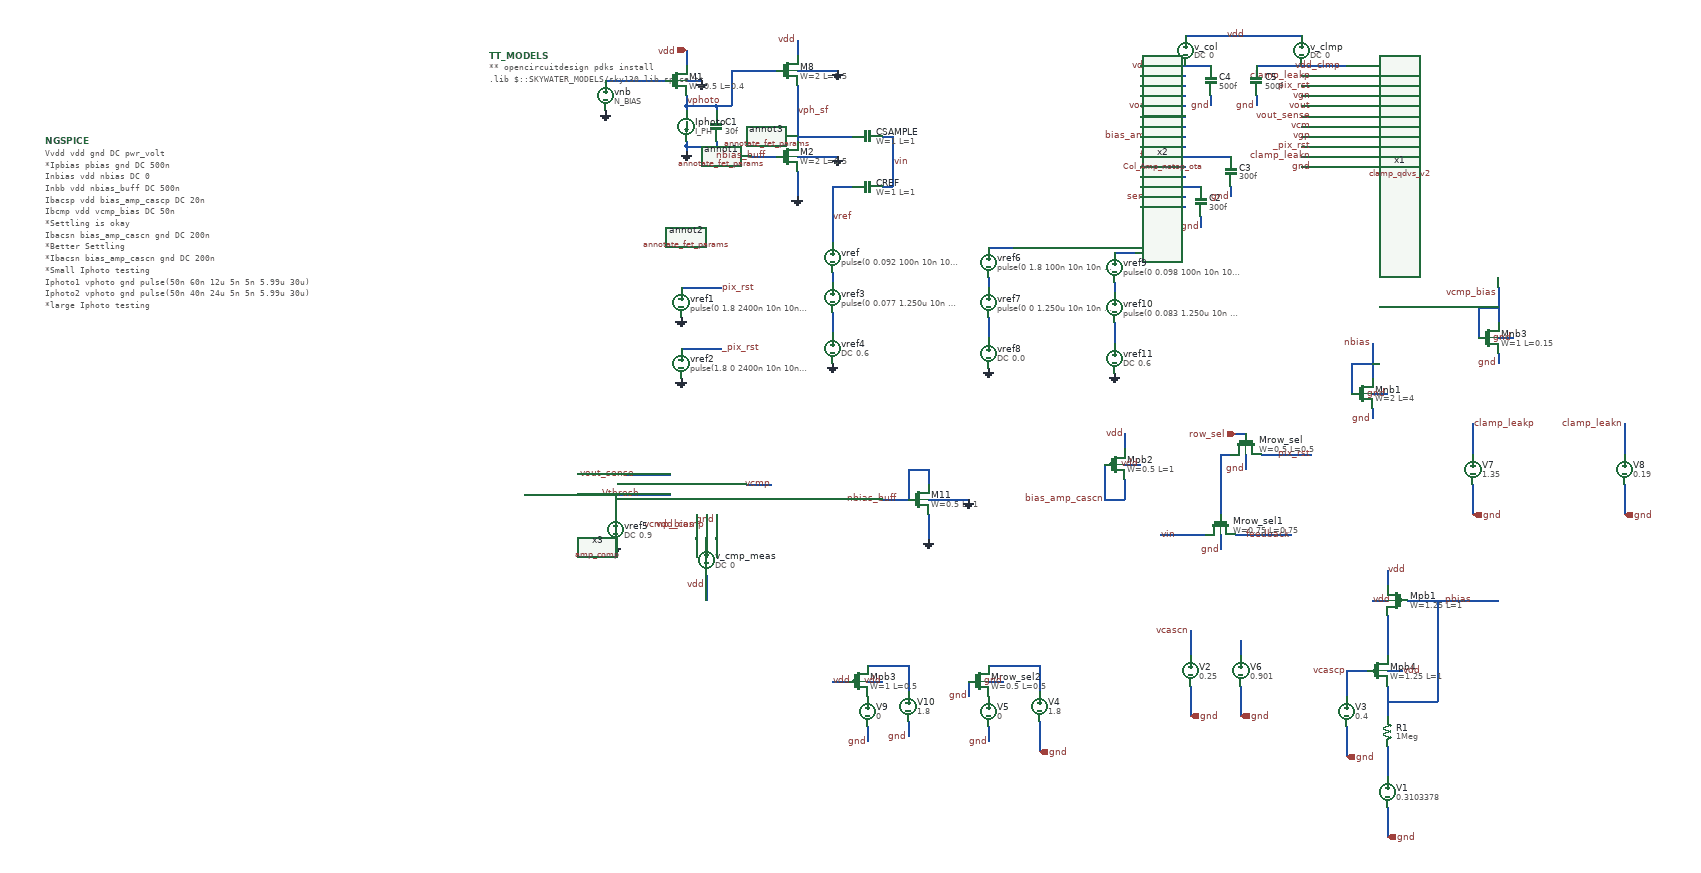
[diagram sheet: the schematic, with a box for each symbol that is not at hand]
v {xschem version=3.4.8RC file_version=1.3}
G {}
K {}
V {}
S {}
F {}
E {}
N -480 -190 -480 -180 {lab=GND}
N -480 -270 -480 -260 {lab=vphoto}
N -480 -380 -480 -350 {lab=vdd}
N -420 -270 -420 -260 {lab=vphoto}
N -480 -270 -420 -270 {lab=vphoto}
N -420 -200 -420 -190 {lab=GND}
N -480 -190 -420 -190 {lab=GND}
N -170 -210 -150 -210 {lab=vph_sf}
N -90 -110 -70 -110 {lab=vin}
N -70 -210 -70 -110 {lab=vin}
N -90 -210 -70 -210 {lab=vin}
N -480 -290 -480 -270 {lab=vphoto}
N -480 -200 -480 -190 {lab=GND}
N -480 -320 -450 -320 {lab=GND}
N -640 -320 -520 -320 {lab=#net1}
N -260 -210 -170 -210 {lab=vph_sf}
N -260 -310 -260 -230 {lab=vph_sf}
N -260 -230 -260 -200 {lab=vph_sf}
N -420 -270 -390 -270 {lab=vphoto}
N -390 -340 -390 -270 {lab=vphoto}
N -390 -340 -300 -340 {lab=vphoto}
N -260 -170 -180 -170 {lab=GND}
N -260 -400 -260 -370 {lab=vdd}
N -260 -140 -260 -90 {lab=GND}
N -350 -170 -300 -170 {lab=nbias_buff}
N -260 -340 -180 -340 {lab=GND}
N -490 90 -410 90 {lab=pix_rst}
N -490 210 -410 210 {lab=_pix_rst}
N -190 60 -190 80 {lab=#net2}
N -190 140 -190 180 {lab=#net3}
N -190 -110 -190 0 {lab=vref}
N -190 -110 -150 -110 {lab=vref}
N 420 -330 510 -330 {lab=pbias}
N 420 -310 510 -310 {lab=pbchk}
N 420 -290 510 -290 {lab=vcascp}
N 420 -270 510 -270 {lab=vout_sense}
N 420 -250 510 -250 {lab=pix_rst}
N 420 -230 510 -230 {lab=vcascn}
N 420 -210 510 -210 {lab=bias_amp_cascn}
N 420 -190 510 -190 {lab=gnd}
N 420 -170 510 -170 {lab=feedback}
N 420 -150 510 -150 {lab=nbias}
N 420 -130 510 -130 {lab=row_sel}
N 420 -110 510 -110 {lab=sense}
N 420 -90 510 -90 {lab=sense_local}
N 420 -70 510 -70 {lab=vin}
N 540 -50 540 -30 {lab=gnd}
N 510 -110 540 -110 {lab=sense}
N 510 -170 600 -170 {lab=feedback}
N 600 -110 600 -90 {lab=gnd}
N 420 -350 510 -350 {lab=vdd_col}
N 880 330 880 350 {lab=gnd}
N 880 300 910 300 {lab=gnd}
N 880 200 880 270 {lab=nbias}
N 840 240 880 240 {lab=nbias}
N 840 240 840 300 {lab=nbias}
N 390 440 420 440 {lab=vdd}
N 350 440 350 510 {lab=bias_amp_cascn}
N 350 510 390 510 {lab=bias_amp_cascn}
N 390 380 390 410 {lab=vdd}
N 390 470 390 510 {lab=bias_amp_cascn}
N 580 450 580 540 {lab=#net4}
N 630 420 630 450 {lab=gnd}
N 580 420 600 420 {lab=#net4}
N 580 420 580 450 {lab=#net4}
N 610 380 630 380 {lab=row_sel}
N 610 380 630 380 {lab=row_sel}
N 660 420 760 420 {lab=pix_rst}
N 580 580 580 610 {lab=gnd}
N 610 580 720 580 {lab=feedback}
N 460 580 550 580 {lab=vin}
N 740 -330 830 -330 {lab=clamp_leakp}
N 740 -310 830 -310 {lab=pix_rst}
N 740 -290 830 -290 {lab=vgn}
N 740 -270 830 -270 {lab=vout}
N 740 -250 830 -250 {lab=vout_sense}
N 740 -230 830 -230 {lab=vcm}
N 740 -210 830 -210 {lab=vgp}
N 740 -190 830 -190 {lab=_pix_rst}
N 740 -170 830 -170 {lab=clamp_leakn}
N 740 -150 830 -150 {lab=gnd}
N 1080 360 1080 420 {lab=clamp_leakp}
N 1380 360 1380 420 {lab=clamp_leakn}
N 740 -350 830 -350 {lab=vdd_clmp}
N 0 450 0 480 {lab=nbias_buff}
N 0 510 80 510 {lab=GND}
N 0 540 0 590 {lab=GND}
N -90 510 -40 510 {lab=nbias_buff}
N -40 450 -40 510 {lab=nbias_buff}
N -40 450 0 450 {lab=nbias_buff}
N -600 460 -510 460 {lab=vout_sense}
N -460 540 -460 590 {lab=vcmp_bias}
N -440 540 -440 600 {lab=vdd_comp}
N -420 540 -420 590 {lab=gnd}
N -440 660 -440 710 {lab=vdd}
N 1130 220 1130 240 {lab=gnd}
N 1130 190 1160 190 {lab=gnd}
N 1130 90 1130 160 {lab=vcmp_bias}
N 1090 130 1130 130 {lab=vcmp_bias}
N 1090 130 1090 190 {lab=vcmp_bias}
N 510 -410 740 -410 {lab=vdd}
N 560 -290 560 -270 {lab=gnd}
N 650 -290 650 -270 {lab=gnd}
N 650 -350 740 -350 {lab=vdd_clmp}
N 510 -350 560 -350 {lab=vdd_col}
N -800 500 -510 500 {lab=Vthresh}
N -620 500 -620 540 {lab=Vthresh}
N 910 650 910 680 {lab=vdd}
N 880 710 910 710 {lab=vdd}
N 950 710 1000 710 {lab=pbias}
N 910 740 910 790 {lab=#net5}
N 1000 710 1020 710 {lab=pbias}
N 1020 710 1130 710 {lab=pbias}
N 910 1000 910 1060 {lab=#net6}
N 910 1120 910 1180 {lab=gnd}
N 910 790 910 820 {lab=#net5}
N 910 850 940 850 {lab=vdd}
N 910 880 910 940 {lab=pbias}
N 1010 710 1010 910 {lab=pbias}
N 910 910 1010 910 {lab=pbias}
N 830 850 870 850 {lab=vcascp}
N 830 960 830 1020 {lab=gnd}
N 830 850 830 900 {lab=vcascp}
N 520 880 520 940 {lab=gnd}
N 520 770 520 820 {lab=vcascn}
N 120 870 150 870 {lab=gnd}
N 80 870 80 900 {lab=gnd}
N 220 950 220 1010 {lab=gnd}
N 220 840 220 890 {lab=#net7}
N 120 840 220 840 {lab=#net7}
N 120 960 120 990 {lab=gnd}
N 620 880 620 940 {lab=gnd}
N 620 790 620 820 {lab=#net8}
N 120 70 120 90 {lab=#net9}
N 120 150 120 190 {lab=#net10}
N 1080 480 1080 540 {lab=gnd}
N 1380 480 1380 540 {lab=gnd}
N 370 80 370 100 {lab=#net11}
N 370 160 370 200 {lab=#net12}
N 370 20 410 20 {lab=#net13}
N 120 10 170 10 {lab=#net14}
N -360 480 -310 480 {lab=vcmp}
N -120 870 -90 870 {lab=vdd}
N -190 870 -160 870 {lab=vdd}
N -120 960 -120 990 {lab=gnd}
N -40 840 -40 890 {lab=#net15}
N -120 840 -40 840 {lab=#net15}
N -40 950 -40 980 {lab=gnd}
C {gnd.sym} -480 -180 0 0 {name=l2 lab=GND}
C {devices/code.sym} -870 -370 0 0 {name=TT_MODELS
only_toplevel=true
format="tcleval( @value )"
value="
** opencircuitdesign pdks install
.lib $::SKYWATER_MODELS/sky130.lib.spice tt
"
spice_ignore=false}
C {code_shown.sym} -1750 -200 0 0 {name=NGSPICE
only_toplevel=true
value="
Vvdd vdd gnd DC pwr_volt

*Ipbias pbias gnd DC 500n
Inbias vdd nbias DC 0
Inbb vdd nbias_buff DC 500n
Ibacsp vdd bias_amp_cascp DC 20n
Ibcmp vdd vcmp_bias DC 50n

*Settling is okay
Ibacsn bias_amp_cascn gnd DC 200n
*Better Settling
*Ibacsn bias_amp_cascn gnd DC 200n

*Small Iphoto testing
Iphoto1 vphoto gnd pulse(50n 60n 12u 5n 5n 5.99u 30u) 
Iphoto2 vphoto gnd pulse(50n 40n 24u 5n 5n 5.99u 30u)

*large Iphoto testing
*Iphoto1 vphoto gnd pulse(5n 5u 12u 5n 5n 5.99u 30u) 
*Iphoto2 vphoto gnd pulse(5n 5p 24u 5n 5n 5.99u 30u)

Vrow row_sel gnd DC 1.8
*Vcascn vcascn gnd DC 0.25
*Vcascp vcascp gnd DC 0.5
Vvcm vcm gnd DC 0.9

.param I_PH = 0
.param N_BIAS = 1.5
.param SF_BIAS = 1.4
.param pwr_volt = 1.8

.option gmin=1e-15 abstol=1e-15 vntol=1e-9 reltol=1e-6 chgtol=1e-16 trtol=7

.control
	
	save all
	op
	print i(V5)
	tran 0.5n 39u 
	plot v(vphoto) v(vph_sf) v(vin) v(vout_sense) v(vref) v(vcmp) v(vcm) v(vout)


	write tran_col_notopota_clmp_pix.raw
.endc
"}
C {devices/launcher.sym} -640 -420 2 1 {name=h1
descr="Annotate OP" 
tclcommand="set show_hidden_texts 1; xschem annotate_op"
}
C {sky130_fd_pr/annotate_fet_params.sym} -480 -130 0 0 {name=annot1 ref=M1}
C {sky130_fd_pr/cap_mim_m3_1.sym} -120 -210 3 0 {name=CSAMPLE model=cap_mim_m3_1 W=1 L=1 MF=8 spiceprefix=X}
C {sky130_fd_pr/cap_mim_m3_1.sym} -120 -110 3 0 {name=CREF model=cap_mim_m3_1 W=1 L=1 MF=2 spiceprefix=X}
C {capa.sym} -420 -230 0 0 {name=C1
m=1
value=30f
footprint=1206
device="ceramic capacitor"}
C {gnd.sym} -450 -320 0 0 {name=l6 lab=GND}
C {sky130_fd_pr/nfet_01v8.sym} -500 -320 0 0 {name=M1
W=0.5
L=0.4
nf=1 
mult=1
ad="expr('int((@nf + 1)/2) * @W / @nf * 0.29')"
pd="expr('2*int((@nf + 1)/2) * (@W / @nf + 0.29)')"
as="expr('int((@nf + 2)/2) * @W / @nf * 0.29')"
ps="expr('2*int((@nf + 2)/2) * (@W / @nf + 0.29)')"
nrd="expr('0.29 / @W ')" nrs="expr('0.29 / @W ')"
sa=0 sb=0 sd=0
model=nfet_01v8
spiceprefix=X
}
C {vsource.sym} -640 -290 0 0 {name=vnb value=N_BIAS savecurrent=false}
C {gnd.sym} -640 -260 0 0 {name=l5 lab=GND}
C {lab_pin.sym} -480 -280 2 0 {name=p1 sig_type=std_logic lab=vphoto}
C {lab_pin.sym} -260 -260 2 0 {name=p2 sig_type=std_logic lab=vph_sf}
C {vsource.sym} -190 30 0 0 {name=vref value="pulse(0 0.092 100n 10n 10n 1.140u 3u)" savecurrent=false}
C {gnd.sym} -190 240 0 0 {name=l12 lab=GND}
C {lab_pin.sym} -70 -160 2 0 {name=p3 sig_type=std_logic lab=vin}
C {isource.sym} -480 -230 0 0 {name=Iphoto value=I_PH}
C {sky130_fd_pr/annotate_fet_params.sym} -480 -10 0 0 {name=annot2 ref=M2}
C {sky130_fd_pr/annotate_fet_params.sym} -370 -10 0 0 {name=annot3 ref=M3}
C {sky130_fd_pr/nfet_01v8.sym} -280 -340 0 0 {name=M8
W=2
L=0.5
nf=1 
mult=1
ad="expr('int((@nf + 1)/2) * @W / @nf * 0.29')"
pd="expr('2*int((@nf + 1)/2) * (@W / @nf + 0.29)')"
as="expr('int((@nf + 2)/2) * @W / @nf * 0.29')"
ps="expr('2*int((@nf + 2)/2) * (@W / @nf + 0.29)')"
nrd="expr('0.29 / @W ')" nrs="expr('0.29 / @W ')"
sa=0 sb=0 sd=0
model=nfet_01v8
spiceprefix=X
}
C {gnd.sym} -180 -170 0 0 {name=l19 lab=GND}
C {gnd.sym} -260 -90 0 0 {name=l21 lab=GND}
C {lab_wire.sym} -320 -170 0 0 {name=p8 sig_type=std_logic lab=nbias_buff}
C {gnd.sym} -180 -340 0 0 {name=l7 lab=GND}
C {vsource.sym} -490 120 0 0 {name=vref1 value="pulse(0 1.8 2400n 10n 10n 390n 3u)" savecurrent=false}
C {gnd.sym} -490 150 0 0 {name=l25 lab=GND}
C {lab_pin.sym} -410 90 2 0 {name=p14 sig_type=std_logic lab=pix_rst}
C {gnd.sym} -490 270 0 0 {name=l29 lab=GND}
C {lab_pin.sym} -410 210 2 0 {name=p16 sig_type=std_logic lab=_pix_rst}
C {vsource.sym} -190 110 0 0 {name=vref3 value="pulse(0 0.077 1.250u 10n 10n 1.140u 3u)" savecurrent=false}
C {vsource.sym} -190 210 0 0 {name=vref4 value="DC 0.6" savecurrent=false}
C {lab_pin.sym} -190 -50 2 0 {name=p18 sig_type=std_logic lab=vref}
C {lab_wire.sym} 510 -330 0 0 {name=p5 sig_type=std_logic lab=pbias}
C {lab_wire.sym} 510 -310 0 0 {name=p6 sig_type=std_logic lab=pbchk}
C {lab_wire.sym} 510 -290 0 0 {name=p7 sig_type=std_logic lab=vcascp}
C {lab_wire.sym} 510 -270 0 0 {name=p11 sig_type=std_logic lab=vout_sense}
C {lab_wire.sym} 510 -210 0 0 {name=p12 sig_type=std_logic lab=bias_amp_cascn}
C {lab_wire.sym} 510 -230 0 0 {name=p13 sig_type=std_logic lab=vcascn}
C {lab_wire.sym} 500 -250 0 0 {name=p15 sig_type=std_logic lab=pix_rst}
C {lab_wire.sym} 510 -190 0 0 {name=p17 sig_type=std_logic lab=gnd}
C {lab_wire.sym} 510 -170 0 0 {name=p19 sig_type=std_logic lab=feedback}
C {lab_wire.sym} 510 -150 0 0 {name=p20 sig_type=std_logic lab=nbias}
C {lab_wire.sym} 510 -130 0 0 {name=p21 sig_type=std_logic lab=row_sel}
C {lab_wire.sym} 510 -110 0 0 {name=p22 sig_type=std_logic lab=sense}
C {lab_wire.sym} 510 -90 0 0 {name=p23 sig_type=std_logic lab=sense_local}
C {lab_wire.sym} 510 -70 0 0 {name=p24 sig_type=std_logic lab=vin}
C {capa.sym} 540 -80 0 0 {name=C2
m=1
value=300f
footprint=1206
device="ceramic capacitor"}
C {lab_wire.sym} 540 -30 0 0 {name=p33 sig_type=std_logic lab=gnd}
C {capa.sym} 600 -140 0 0 {name=C3
m=1
value=300f
footprint=1206
device="ceramic capacitor"}
C {lab_wire.sym} 600 -90 0 0 {name=p25 sig_type=std_logic lab=gnd}
C {sky130_fd_pr/nfet_01v8.sym} 860 300 0 0 {name=Mnb1
W=2
L=4
nf=1 
mult=1
ad="expr('int((@nf + 1)/2) * @W / @nf * 0.29')"
pd="expr('2*int((@nf + 1)/2) * (@W / @nf + 0.29)')"
as="expr('int((@nf + 2)/2) * @W / @nf * 0.29')"
ps="expr('2*int((@nf + 2)/2) * (@W / @nf + 0.29)')"
nrd="expr('0.29 / @W ')" nrs="expr('0.29 / @W ')"
sa=0 sb=0 sd=0
model=nfet_01v8
spiceprefix=X
}
C {lab_wire.sym} 880 350 0 0 {name=p36 sig_type=std_logic lab=gnd}
C {lab_wire.sym} 910 300 0 0 {name=p37 sig_type=std_logic lab=gnd}
C {lab_wire.sym} 880 200 0 0 {name=p39 sig_type=std_logic lab=nbias}
C {lab_wire.sym} 390 380 0 0 {name=p45 sig_type=std_logic lab=vdd}
C {sky130_fd_pr/pfet_01v8.sym} 370 440 0 0 {name=Mpb2
W=0.5
L=1
nf=1
mult=4
ad="expr('int((@nf + 1)/2) * @W / @nf * 0.29')"
pd="expr('2*int((@nf + 1)/2) * (@W / @nf + 0.29)')"
as="expr('int((@nf + 2)/2) * @W / @nf * 0.29')"
ps="expr('2*int((@nf + 2)/2) * (@W / @nf + 0.29)')"
nrd="expr('0.29 / @W ')" nrs="expr('0.29 / @W ')"
sa=0 sb=0 sd=0
model=pfet_01v8
spiceprefix=X
}
C {lab_wire.sym} 350 510 0 0 {name=p28 sig_type=std_logic lab=bias_amp_cascn}
C {lab_wire.sym} 420 440 0 0 {name=p29 sig_type=std_logic lab=vdd}
C {lab_wire.sym} 630 450 0 0 {name=p48 sig_type=std_logic lab=gnd}
C {iopin.sym} 610 380 2 0 {name=p49 lab=row_sel}
C {sky130_fd_pr/nfet_01v8.sym} 630 400 1 0 {name=Mrow_sel
W=0.5
L=0.5
nf=1 
mult=1
ad="expr('int((@nf + 1)/2) * @W / @nf * 0.29')"
pd="expr('2*int((@nf + 1)/2) * (@W / @nf + 0.29)')"
as="expr('int((@nf + 2)/2) * @W / @nf * 0.29')"
ps="expr('2*int((@nf + 2)/2) * (@W / @nf + 0.29)')"
nrd="expr('0.29 / @W ')" nrs="expr('0.29 / @W ')"
sa=0 sb=0 sd=0
model=nfet_01v8
spiceprefix=X
}
C {lab_wire.sym} 720 580 0 0 {name=p51 sig_type=std_logic lab=feedback}
C {lab_wire.sym} 580 610 0 0 {name=p52 sig_type=std_logic lab=gnd}
C {sky130_fd_pr/nfet_01v8.sym} 580 560 1 0 {name=Mrow_sel1
W=0.75
L=0.75
nf=1 
mult=1
ad="expr('int((@nf + 1)/2) * @W / @nf * 0.29')"
pd="expr('2*int((@nf + 1)/2) * (@W / @nf + 0.29)')"
as="expr('int((@nf + 2)/2) * @W / @nf * 0.29')"
ps="expr('2*int((@nf + 2)/2) * (@W / @nf + 0.29)')"
nrd="expr('0.29 / @W ')" nrs="expr('0.29 / @W ')"
sa=0 sb=0 sd=0
model=nfet_01v8
spiceprefix=X
}
C {lab_wire.sym} 460 580 0 1 {name=p53 sig_type=std_logic lab=vin}
C {lab_wire.sym} 760 420 0 0 {name=p55 sig_type=std_logic lab=pix_rst}
C {/home/user/projects/open_dvs/analog/clamp_qdvs_v2.sym} 980 -250 0 1 {name=x1}
C {lab_wire.sym} 760 -330 0 0 {name=p26 sig_type=std_logic lab=clamp_leakp}
C {lab_wire.sym} 760 -310 0 0 {name=p30 sig_type=std_logic lab=pix_rst}
C {lab_wire.sym} 760 -290 0 0 {name=p31 sig_type=std_logic lab=vgn}
C {lab_wire.sym} 760 -270 0 0 {name=p32 sig_type=std_logic lab=vout}
C {lab_wire.sym} 760 -230 0 0 {name=p34 sig_type=std_logic lab=vcm}
C {lab_wire.sym} 760 -210 0 0 {name=p35 sig_type=std_logic lab=vgp}
C {lab_wire.sym} 760 -190 0 0 {name=p43 sig_type=std_logic lab=_pix_rst}
C {lab_wire.sym} 760 -170 0 0 {name=p44 sig_type=std_logic lab=clamp_leakn}
C {lab_wire.sym} 760 -150 0 0 {name=p47 sig_type=std_logic lab=gnd}
C {lab_pin.sym} 1080 360 2 0 {name=p57 sig_type=std_logic lab=clamp_leakp
}
C {lab_pin.sym} 1380 360 0 0 {name=p60 sig_type=std_logic lab=clamp_leakn
}
C {sky130_fd_pr/nfet_01v8.sym} -20 510 0 0 {name=M11
W=0.5
L=1
nf=1 
mult=1
ad="expr('int((@nf + 1)/2) * @W / @nf * 0.29')"
pd="expr('2*int((@nf + 1)/2) * (@W / @nf + 0.29)')"
as="expr('int((@nf + 2)/2) * @W / @nf * 0.29')"
ps="expr('2*int((@nf + 2)/2) * (@W / @nf + 0.29)')"
nrd="expr('0.29 / @W ')" nrs="expr('0.29 / @W ')"
sa=0 sb=0 sd=0
model=nfet_01v8
spiceprefix=X
}
C {gnd.sym} 80 510 0 0 {name=l23 lab=GND}
C {gnd.sym} 0 590 0 0 {name=l24 lab=GND}
C {lab_wire.sym} -60 510 0 0 {name=p4 sig_type=std_logic lab=nbias_buff}
C {lab_wire.sym} -580 460 0 0 {name=p63 sig_type=std_logic lab=vout_sense}
C {lab_wire.sym} -310 480 0 0 {name=p64 sig_type=std_logic lab=vcmp}
C {lab_wire.sym} -460 560 3 0 {name=p65 sig_type=std_logic lab=vcmp_bias}
C {lab_wire.sym} -440 680 3 0 {name=p66 sig_type=std_logic lab=vdd}
C {lab_wire.sym} -420 550 1 1 {name=p67 sig_type=std_logic lab=gnd}
C {sky130_fd_pr/nfet_01v8.sym} 1110 190 0 0 {name=Mnb3
W=1
L=0.15
nf=1 
mult=1
ad="expr('int((@nf + 1)/2) * @W / @nf * 0.29')"
pd="expr('2*int((@nf + 1)/2) * (@W / @nf + 0.29)')"
as="expr('int((@nf + 2)/2) * @W / @nf * 0.29')"
ps="expr('2*int((@nf + 2)/2) * (@W / @nf + 0.29)')"
nrd="expr('0.29 / @W ')" nrs="expr('0.29 / @W ')"
sa=0 sb=0 sd=0
model=nfet_01v8
spiceprefix=X
}
C {lab_wire.sym} 1130 240 0 0 {name=p68 sig_type=std_logic lab=gnd}
C {lab_wire.sym} 1160 190 0 0 {name=p69 sig_type=std_logic lab=gnd}
C {lab_wire.sym} 1130 100 0 0 {name=p71 sig_type=std_logic lab=vcmp_bias}
C {vsource.sym} 510 -380 0 0 {name=v_col value="DC 0" savecurrent=true}
C {vsource.sym} 740 -380 0 0 {name=v_clmp value="DC 0" savecurrent=true}
C {vsource.sym} -440 630 2 0 {name=v_cmp_meas value="DC 0" savecurrent=true}
C {iopin.sym} -480 -380 0 0 {name=p70 lab=vdd}
C {lab_wire.sym} -260 -400 0 0 {name=p72 sig_type=std_logic lab=vdd}
C {lab_wire.sym} 630 -410 0 0 {name=p73 sig_type=std_logic lab=vdd}
C {lab_wire.sym} 480 -350 0 0 {name=p74 sig_type=std_logic lab=vdd_col}
C {lab_wire.sym} 820 -350 0 0 {name=p75 sig_type=std_logic lab=vdd_clmp}
C {lab_wire.sym} -440 560 3 0 {name=p76 sig_type=std_logic lab=vdd_comp}
C {capa.sym} 560 -320 0 0 {name=C4
m=1
value=500f
footprint=1206
device="ceramic capacitor"}
C {lab_wire.sym} 560 -270 0 0 {name=p77 sig_type=std_logic lab=gnd}
C {capa.sym} 650 -320 0 0 {name=C5
m=1
value=500f
footprint=1206
device="ceramic capacitor"}
C {lab_wire.sym} 650 -270 0 0 {name=p78 sig_type=std_logic lab=gnd}
C {sky130_fd_pr/nfet_01v8.sym} -280 -170 0 0 {name=M2
W=2
L=0.5
nf=1 
mult=1
ad="expr('int((@nf + 1)/2) * @W / @nf * 0.29')"
pd="expr('2*int((@nf + 1)/2) * (@W / @nf + 0.29)')"
as="expr('int((@nf + 2)/2) * @W / @nf * 0.29')"
ps="expr('2*int((@nf + 2)/2) * (@W / @nf + 0.29)')"
nrd="expr('0.29 / @W ')" nrs="expr('0.29 / @W ')"
sa=0 sb=0 sd=0
model=nfet_01v8
spiceprefix=X
}
C {vsource.sym} -490 240 0 0 {name=vref2 value="pulse(1.8 0 2400n 10n 10n 390n 3u)" savecurrent=false}
C {/home/user/projects/open_dvs/analog/Col_Amp_notop_ota.sym} 270 -210 0 0 {name=x2}
C {lab_wire.sym} -570 500 0 0 {name=p79 sig_type=std_logic lab=Vthresh}
C {gnd.sym} -620 600 0 0 {name=l3 lab=GND}
C {vsource.sym} -620 570 0 0 {name=vref5 value="DC 0.9" savecurrent=false}
C {lab_wire.sym} 760 -250 0 0 {name=p9 sig_type=std_logic lab=vout_sense}
C {lab_wire.sym} 880 710 0 1 {name=p10 sig_type=std_logic lab=vdd}
C {sky130_fd_pr/pfet_01v8.sym} 930 710 0 1 {name=Mpb1
W=1.25
L=1
nf=1
mult=4
ad="expr('int((@nf + 1)/2) * @W / @nf * 0.29')"
pd="expr('2*int((@nf + 1)/2) * (@W / @nf + 0.29)')"
as="expr('int((@nf + 2)/2) * @W / @nf * 0.29')"
ps="expr('2*int((@nf + 2)/2) * (@W / @nf + 0.29)')"
nrd="expr('0.29 / @W ')" nrs="expr('0.29 / @W ')"
sa=0 sb=0 sd=0
model=pfet_01v8
spiceprefix=X
}
C {lab_wire.sym} 910 650 0 1 {name=p27 sig_type=std_logic lab=vdd}
C {res.sym} 910 970 0 0 {name=R1
value=1Meg
footprint=1206
device=resistor
m=1}
C {vsource.sym} 910 1090 0 0 {name=V1 value=0.3103378 savecurrent=true}
C {iopin.sym} 910 1180 2 1 {name=p38 lab=gnd}
C {sky130_fd_pr/pfet_01v8.sym} 890 850 0 0 {name=Mpb4
W=1.25
L=1
nf=1
mult=4
ad="expr('int((@nf + 1)/2) * @W / @nf * 0.29')"
pd="expr('2*int((@nf + 1)/2) * (@W / @nf + 0.29)')"
as="expr('int((@nf + 2)/2) * @W / @nf * 0.29')"
ps="expr('2*int((@nf + 2)/2) * (@W / @nf + 0.29)')"
nrd="expr('0.29 / @W ')" nrs="expr('0.29 / @W ')"
sa=0 sb=0 sd=0
model=pfet_01v8
spiceprefix=X
}
C {lab_wire.sym} 940 850 0 1 {name=p42 sig_type=std_logic lab=vdd}
C {lab_wire.sym} 1080 710 0 0 {name=p80 sig_type=std_logic lab=pbias}
C {vsource.sym} 830 930 0 0 {name=V3 value=0.4 savecurrent=true}
C {iopin.sym} 830 1020 2 1 {name=p40 lab=gnd}
C {lab_wire.sym} 830 850 0 0 {name=p41 sig_type=std_logic lab=vcascp}
C {vsource.sym} 520 850 0 0 {name=V2 value=0.25 savecurrent=true}
C {iopin.sym} 520 940 2 1 {name=p46 lab=gnd}
C {lab_wire.sym} 520 770 0 0 {name=p50 sig_type=std_logic lab=vcascn}
C {sky130_fd_pr/nfet_01v8.sym} 100 870 0 0 {name=Mrow_sel2
W=0.5
L=0.5
nf=1 
mult=1
ad="expr('int((@nf + 1)/2) * @W / @nf * 0.29')"
pd="expr('2*int((@nf + 1)/2) * (@W / @nf + 0.29)')"
as="expr('int((@nf + 2)/2) * @W / @nf * 0.29')"
ps="expr('2*int((@nf + 2)/2) * (@W / @nf + 0.29)')"
nrd="expr('0.29 / @W ')" nrs="expr('0.29 / @W ')"
sa=0 sb=0 sd=0
model=nfet_01v8
spiceprefix=X
}
C {lab_wire.sym} 150 870 3 0 {name=p81 sig_type=std_logic lab=gnd}
C {lab_wire.sym} 80 900 0 0 {name=p83 sig_type=std_logic lab=gnd}
C {vsource.sym} 220 920 0 0 {name=V4 value=1.8 savecurrent=true}
C {iopin.sym} 220 1010 2 1 {name=p84 lab=gnd}
C {lab_wire.sym} 120 990 0 0 {name=p85 sig_type=std_logic lab=gnd}
C {vsource.sym} 120 930 0 0 {name=V5 value=0 savecurrent=true}
C {vsource.sym} 620 850 0 0 {name=V6 value=0.901 savecurrent=true}
C {iopin.sym} 620 940 2 1 {name=p82 lab=gnd}
C {vsource.sym} 120 40 0 0 {name=vref6 value="pulse(0 1.8 100n 10n 10n 1.140u 3u)" savecurrent=false}
C {gnd.sym} 120 250 0 0 {name=l1 lab=GND}
C {vsource.sym} 120 120 0 0 {name=vref7 value="pulse(0 0 1.250u 10n 10n 1.140u 3u)" savecurrent=false}
C {vsource.sym} 120 220 0 0 {name=vref8 value="DC 0.0" savecurrent=false}
C {vsource.sym} 1080 450 0 0 {name=V7 value=1.35 savecurrent=true}
C {iopin.sym} 1080 540 2 1 {name=p56 lab=gnd}
C {vsource.sym} 1380 450 0 0 {name=V8 value=0.19 savecurrent=true}
C {iopin.sym} 1380 540 2 1 {name=p58 lab=gnd}
C {/home/user/projects/nic2025_v2/nic2025_openDVS/analog/xschem/amp_comp.sym} -510 550 0 0 {name=x3}
C {vsource.sym} 370 50 0 0 {name=vref9 value="pulse(0 0.098 100n 10n 10n 1.140u 3u)" savecurrent=false}
C {gnd.sym} 370 260 0 0 {name=l4 lab=GND}
C {vsource.sym} 370 130 0 0 {name=vref10 value="pulse(0 0.083 1.250u 10n 10n 1.140u 3u)" savecurrent=false}
C {vsource.sym} 370 230 0 0 {name=vref11 value="DC 0.6" savecurrent=false}
C {sky130_fd_pr/pfet_01v8.sym} -140 870 0 0 {name=Mpb3
W=1
L=0.5
nf=1
mult=1
ad="expr('int((@nf + 1)/2) * @W / @nf * 0.29')"
pd="expr('2*int((@nf + 1)/2) * (@W / @nf + 0.29)')"
as="expr('int((@nf + 2)/2) * @W / @nf * 0.29')"
ps="expr('2*int((@nf + 2)/2) * (@W / @nf + 0.29)')"
nrd="expr('0.29 / @W ')" nrs="expr('0.29 / @W ')"
sa=0 sb=0 sd=0
model=pfet_01v8
spiceprefix=X
}
C {lab_wire.sym} -90 870 0 0 {name=p54 sig_type=std_logic lab=vdd}
C {lab_wire.sym} -190 870 0 1 {name=p61 sig_type=std_logic lab=vdd}
C {vsource.sym} -120 930 0 0 {name=V9 value=0 savecurrent=true}
C {lab_wire.sym} -120 990 0 0 {name=p62 sig_type=std_logic lab=gnd}
C {vsource.sym} -40 920 0 0 {name=V10 value=1.8 savecurrent=true}
C {lab_wire.sym} -40 980 0 0 {name=p59 sig_type=std_logic lab=gnd}
